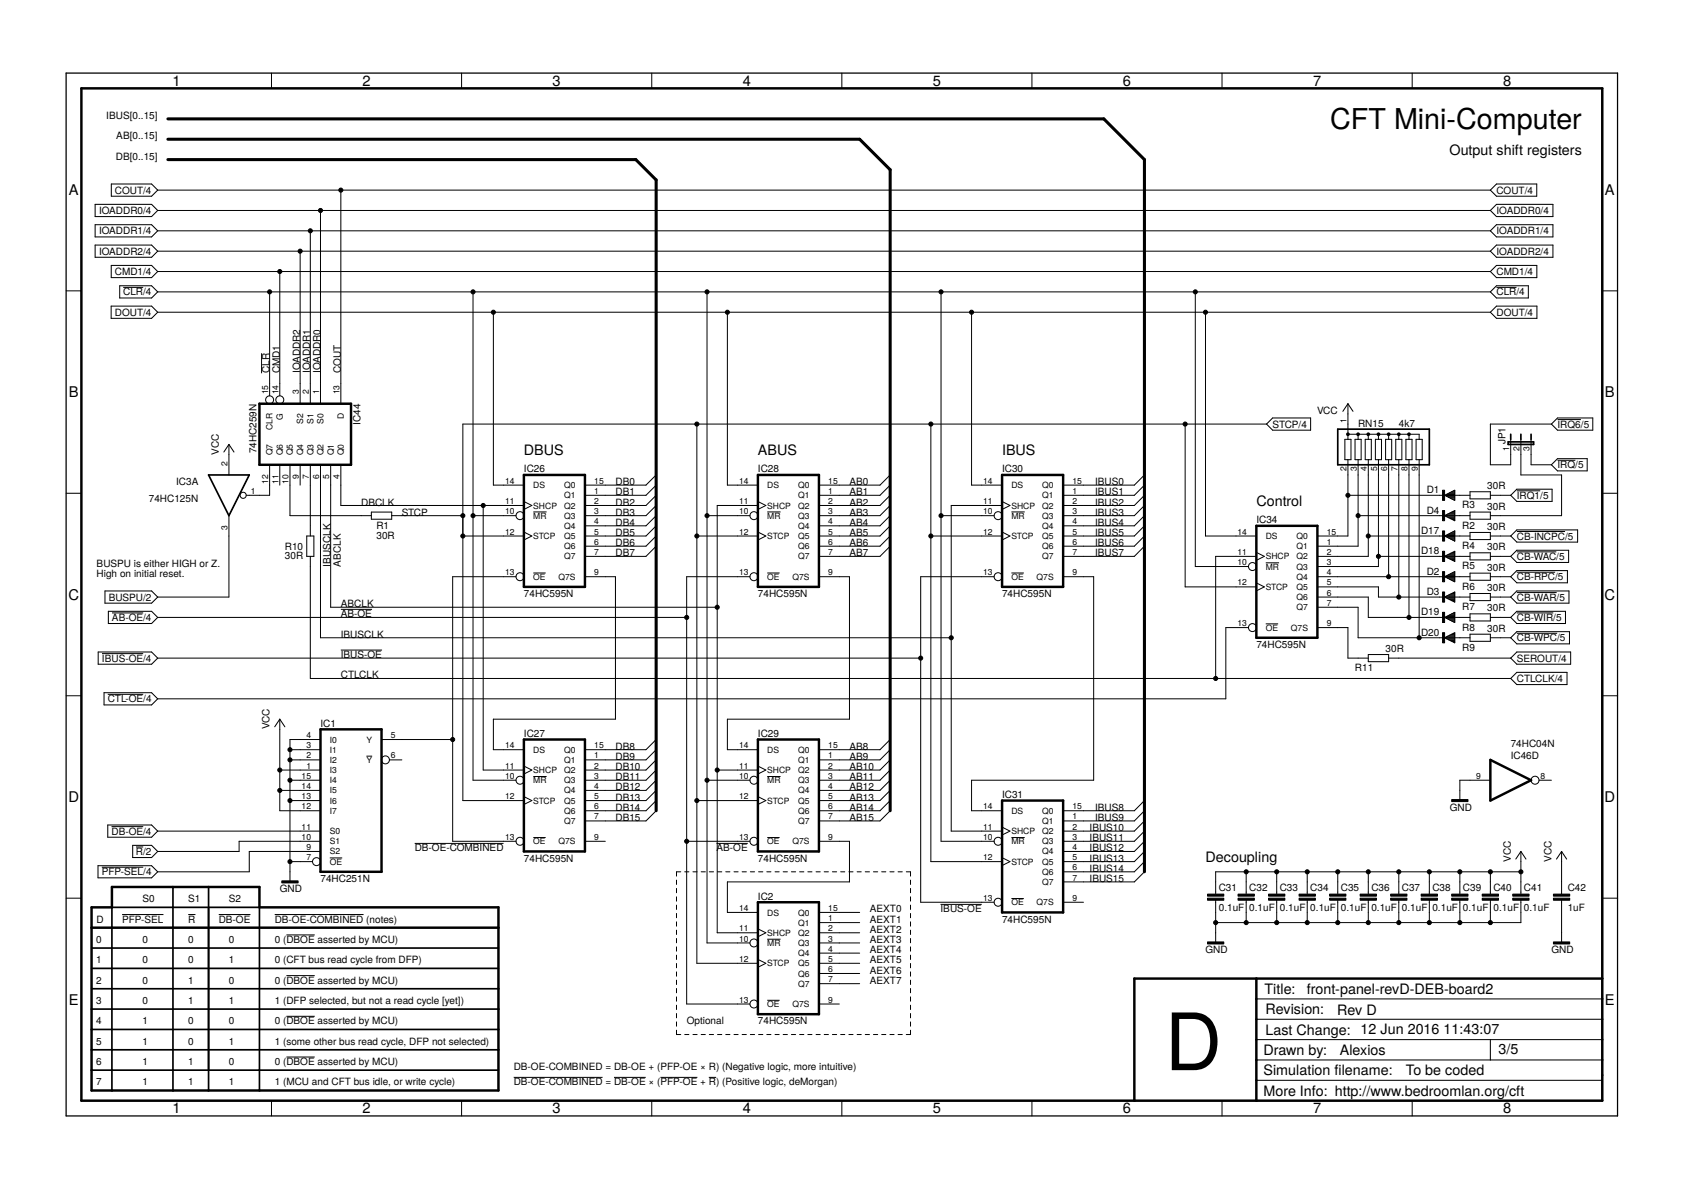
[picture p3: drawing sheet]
<svg xmlns="http://www.w3.org/2000/svg" width="420mm" height="297mm" viewBox="0 0 420 297" stroke-linecap="round" stroke-linejoin="round" font-family="sans-serif">
<defs><g id="words">
<text font-size="19.7" x="290.8" y="267.1">D</text>
<text font-size="7.2" x="332.1" y="32.2">CFT Mini-Computer</text>
<g font-size="3.7">
<text x="43" y="21.4">1</text>
<text x="90.5" y="21.4">2</text>
<text x="138" y="21.4">3</text>
<text x="185.4" y="21.4">4</text>
<text x="232.9" y="21.4">5</text>
<text x="280.3" y="21.4">6</text>
<text x="327.8" y="21.4">7</text>
<text x="375.3" y="21.4">8</text>
<text x="17.2" y="48.6">A</text>
<text x="400.7" y="48.6">A</text>
<text x="17.2" y="99.2">B</text>
<text x="400.7" y="99.2">B</text>
<text x="17.1" y="149.7">C</text>
<text x="400.6" y="149.7">C</text>
<text x="17.1" y="200.2">D</text>
<text x="400.6" y="200.2">D</text>
<text x="17.2" y="250.8">E</text>
<text x="400.7" y="250.8">E</text>
<text x="43" y="277.9">1</text>
<text x="90.5" y="277.9">2</text>
<text x="138" y="277.9">3</text>
<text x="185.4" y="277.9">4</text>
<text x="232.9" y="277.9">5</text>
<text x="280.3" y="277.9">6</text>
<text x="327.8" y="277.9">7</text>
<text x="375.3" y="277.9">8</text>
</g>
<g font-size="3.6">
<text x="361.9" y="38.6">Output shift registers</text>
<text x="130.8" y="113.5">DBUS</text>
<text x="189.2" y="113.5">ABUS</text>
<text x="250.2" y="113.5">IBUS</text>
<text x="313.7" y="126.2">Control</text>
<text x="301" y="215.1">Decoupling</text>
<text x="315.7" y="248.1">Title:</text>
<text x="326.2" y="248.2">front-panel-revD-DEB-board2</text>
<text x="315.9" y="253.2">Revision:</text>
<text x="333.8" y="253.3">Rev D</text>
<text x="315.4" y="263.3">Drawn by:</text>
<text x="315.9" y="258.2">Last Change: 12 Jun 2016</text>
<text x="334.5" y="263.3">Alexios</text>
<text x="360.4" y="258.1">11:43:07</text>
<text x="374.1" y="263.2">3/5</text>
<text x="315.4" y="268.4">Simulation flename:</text>
<text x="333.2" y="268.4">i</text>
<text x="351" y="268.4">To be coded</text>
<text x="315.4" y="273.5">More Info: http://www.bedroomlan.org/cft</text>
</g>
<g font-size="2.5">
<text x="26.5" y="29.7">IBUS[0..15]</text>
<text x="29" y="34.8">AB[0..15]</text>
<text x="28.9" y="39.8">DB[0..15]</text>
<text x="24.7" y="53.4">IOADDR0/4</text>
<text x="28.7" y="48.3">COUT/4</text>
<text x="373.6" y="53.4">IOADDR0/4</text>
<text x="373.6" y="48.3">COUT/4</text>
<text x="24.7" y="58.5">IOADDR1/4</text>
<text x="373.6" y="58.5">IOADDR1/4</text>
<text x="24.7" y="63.6">IOADDR2/4</text>
<text x="373.6" y="63.6">IOADDR2/4</text>
<text x="28.7" y="68.7">CMD1/4</text>
<text x="373.6" y="68.7">CMD1/4</text>
<text x="30.8" y="73.7">CLR/4</text>
<text x="373.6" y="73.7">CLR/4</text>
<text x="28.7" y="78.8">DOUT/4</text>
<text x="373.6" y="78.8">DOUT/4</text>
<text x="67.3" y="93.2" transform="rotate(-90 67.3 93.2)">CLR</text>
<text x="69.8" y="93.2" transform="rotate(-90 69.8 93.2)">CMD1</text>
<text x="74.9" y="93.2" transform="rotate(-90 74.9 93.2)">IOADDR2</text>
<text x="77.5" y="93.2" transform="rotate(-90 77.5 93.2)">IOADDR1</text>
<text x="80" y="93.2" transform="rotate(-90 80 93.2)">IOADDR0</text>
<text x="85.1" y="93.2" transform="rotate(-90 85.1 93.2)">COUT</text>
<text x="90" y="106.1" transform="rotate(-90 90 106.1)">IC44</text>
<text x="317.7" y="106.8">STCP/4</text>
<text x="328.8" y="103.3">VCC</text>
<text x="339.1" y="106.5">RN15</text>
<text x="349.2" y="106.5">4k7</text>
<text x="388.8" y="106.8">IRQ6/5</text>
<text x="54.6" y="113.5" transform="rotate(-90 54.6 113.5)">VCC</text>
<text x="64" y="113.2" transform="rotate(-90 64 113.2)">74HC259N</text>
<text x="375.9" y="110.9" transform="rotate(-90 375.9 110.9)">JP1</text>
<text x="130.8" y="117.9">IC26</text>
<text x="189.2" y="117.9">IC28</text>
<text x="250.2" y="117.9">IC30</text>
<text x="388.8" y="116.9">IRQ/5</text>
<text x="37.1" y="125.4">74HC125N</text>
<text x="44" y="121">IC3A</text>
<text x="153.7" y="121.1">DB0</text>
<text x="153.7" y="123.6">DB1</text>
<text x="212.1" y="121.1">AB0</text>
<text x="212.1" y="123.6">AB1</text>
<text x="273.4" y="121.1">IBUS0</text>
<text x="273.4" y="123.6">IBUS1</text>
<text x="356.2" y="123.2">D1</text>
<text x="371.3" y="122.1">30R</text>
<text x="378.7" y="124.5">IRQ1/5</text>
<text x="90.2" y="126.2">DBCLK</text>
<text x="94" y="132">R1</text>
<text x="100.3" y="128.7">STCP</text>
<text x="153.7" y="126.2">DB2</text>
<text x="153.7" y="128.7">DB3</text>
<text x="153.7" y="131.3">DB4</text>
<text x="212.1" y="126.2">AB2</text>
<text x="212.1" y="128.7">AB3</text>
<text x="212.1" y="131.3">AB4</text>
<text x="273.4" y="126.2">IBUS2</text>
<text x="273.4" y="128.7">IBUS3</text>
<text x="273.4" y="131.3">IBUS4</text>
<text x="313.7" y="130.6">IC34</text>
<text x="356.2" y="128.2">D4</text>
<text x="365.1" y="132">R2</text>
<text x="365.1" y="126.9">R3</text>
<text x="371.3" y="127.2">30R</text>
<text x="71.1" y="137.4">R10</text>
<text x="94" y="134.6">30R</text>
<text x="153.7" y="133.8">DB5</text>
<text x="153.7" y="136.3">DB6</text>
<text x="212.1" y="133.8">AB5</text>
<text x="212.1" y="136.3">AB6</text>
<text x="273.4" y="133.8">IBUS5</text>
<text x="273.4" y="136.3">IBUS6</text>
<text x="354.8" y="133.3">D17</text>
<text x="365.1" y="137.1">R4</text>
<text x="371.3" y="132.3">30R</text>
<text x="371.3" y="137.4">30R</text>
<text x="378.7" y="134.7">CB-INCPC/5</text>
<text x="24.1" y="141.4">BUSPU is either HIGH or Z.</text>
<text x="24.1" y="144">High on initial reset.</text>
<text x="71.1" y="139.6">30R</text>
<text x="82.5" y="141.4" transform="rotate(-90 82.5 141.4)">IBUSCLK</text>
<text x="85.1" y="141.4" transform="rotate(-90 85.1 141.4)">ABCLK</text>
<text x="153.7" y="138.9">DB7</text>
<text x="212.1" y="138.9">AB7</text>
<text x="273.4" y="138.9">IBUS7</text>
<text x="354.8" y="138.4">D18</text>
<text x="356.2" y="143.5">D2</text>
<text x="365.1" y="142.2">R5</text>
<text x="371.3" y="142.4">30R</text>
<text x="378.7" y="139.8">CB-WAC/5</text>
<text x="27.1" y="149.9">BUSPU/2</text>
<text x="130.8" y="149">74HC595N</text>
<text x="189.2" y="149">74HC595N</text>
<text x="250.2" y="149">74HC595N</text>
<text x="356.2" y="148.6">D3</text>
<text x="365.1" y="147.2">R6</text>
<text x="371.3" y="147.5">30R</text>
<text x="378.7" y="149.9">CB-WAR/5</text>
<text x="378.7" y="144.8">CB-RPC/5</text>
<text x="28" y="155">AB-OE/4</text>
<text x="85.1" y="151.6">ABCLK</text>
<text x="85.1" y="154.1">AB-OE</text>
<text x="354.8" y="153.6">D19</text>
<text x="365.1" y="152.3">R7</text>
<text x="371.3" y="152.6">30R</text>
<text x="378.7" y="155">CB-WIR/5</text>
<text x="85.1" y="159.2">IBUSCLK</text>
<text x="313.7" y="161.7">74HC595N</text>
<text x="354.8" y="158.7">D20</text>
<text x="365.1" y="157.4">R8</text>
<text x="371.3" y="157.7">30R</text>
<text x="378.7" y="160.1">CB-WPC/5</text>
<text x="25.5" y="165.2">IBUS-OE/4</text>
<text x="85.1" y="164.3">IBUS-OE</text>
<text x="338.3" y="167.5">R11</text>
<text x="345.9" y="162.8">30R</text>
<text x="365.1" y="162.5">R9</text>
<text x="378.7" y="165.2">SEROUT/4</text>
<text x="85.1" y="169.4">CTLCLK</text>
<text x="378.7" y="170.2">CTLCLK/4</text>
<text x="26.9" y="175.3">CTL-OE/4</text>
<text x="67.3" y="182.1" transform="rotate(-90 67.3 182.1)">VCC</text>
<text x="80" y="181.4">IC1</text>
<text x="130.8" y="184">IC27</text>
<text x="189.2" y="184">IC29</text>
<text x="153.7" y="187.1">DB8</text>
<text x="153.7" y="189.7">DB9</text>
<text x="212.1" y="187.1">AB8</text>
<text x="212.1" y="189.7">AB9</text>
<text x="377.1" y="186.4">74HC04N</text>
<text x="377.1" y="189.5">IC46D</text>
<text x="153.7" y="192.2">DB10</text>
<text x="153.7" y="194.7">DB11</text>
<text x="153.7" y="197.3">DB12</text>
<text x="212.1" y="192.2">AB10</text>
<text x="212.1" y="194.7">AB11</text>
<text x="212.1" y="197.3">AB12</text>
<text x="153.7" y="199.8">DB13</text>
<text x="153.7" y="202.4">DB14</text>
<text x="212.1" y="199.8">AB13</text>
<text x="212.1" y="202.4">AB14</text>
<text x="250.2" y="199.2">IC31</text>
<text x="273.4" y="202.4">IBUS8</text>
<text x="361.9" y="202.4">GND</text>
<text x="27.8" y="208.3">DB-OE/4</text>
<text x="153.7" y="204.9">DB15</text>
<text x="212.1" y="204.9">AB15</text>
<text x="272" y="207.4">IBUS10</text>
<text x="272" y="210">IBUS11</text>
<text x="273.4" y="204.9">IBUS9</text>
<text x="33.9" y="213.4">R/2</text>
<text x="103.5" y="212.5">DB-OE-COMBINED</text>
<text x="130.8" y="215.1">74HC595N</text>
<text x="178.9" y="212.5">AB-OE</text>
<text x="189.2" y="215.1">74HC595N</text>
<text x="272" y="212.5">IBUS12</text>
<text x="272" y="215.1">IBUS13</text>
<text x="377.1" y="215.1" transform="rotate(-90 377.1 215.1)">VCC</text>
<text x="387.3" y="215.1" transform="rotate(-90 387.3 215.1)">VCC</text>
<text x="25.4" y="218.5">PFP-SEL/4</text>
<text x="80" y="220.1">74HC251N</text>
<text x="272" y="217.6">IBUS14</text>
<text x="272" y="220.1">IBUS15</text>
<text x="35.6" y="225.2">S0</text>
<text x="47" y="225.2">S1</text>
<text x="57.1" y="225.2">S2</text>
<text x="69.8" y="222.7">GND</text>
<text x="189.2" y="224.6">IC2</text>
<text x="217.1" y="227.8">AEXT0</text>
<text x="234.8" y="227.8">IBUS-OE</text>
<text x="304.3" y="227.4">0.1uF</text>
<text x="304.3" y="222.3">C31</text>
<text x="311.9" y="227.4">0.1uF</text>
<text x="311.9" y="222.3">C32</text>
<text x="319.5" y="227.4">0.1uF</text>
<text x="319.5" y="222.3">C33</text>
<text x="327.1" y="227.4">0.1uF</text>
<text x="327.1" y="222.3">C34</text>
<text x="334.7" y="227.4">0.1uF</text>
<text x="334.7" y="222.3">C35</text>
<text x="342.4" y="227.4">0.1uF</text>
<text x="342.4" y="222.3">C36</text>
<text x="350" y="227.4">0.1uF</text>
<text x="350" y="222.3">C37</text>
<text x="357.6" y="227.4">0.1uF</text>
<text x="357.6" y="222.3">C38</text>
<text x="365.2" y="227.4">0.1uF</text>
<text x="365.2" y="222.3">C39</text>
<text x="372.8" y="227.4">0.1uF</text>
<text x="372.8" y="222.3">C40</text>
<text x="380.4" y="227.4">0.1uF</text>
<text x="380.4" y="222.3">C41</text>
<text x="391.4" y="227.4">1uF</text>
<text x="391.4" y="222.3">C42</text>
<text x="24.1" y="230.3">D</text>
<text x="30.5" y="230.3">PFP-SEL</text>
<text x="47" y="230.3">R</text>
<text x="54.6" y="230.3">DB-OE</text>
<text x="68.6" y="230.3">DB-OE-COMBINED (notes)</text>
<text x="217.1" y="230.3">AEXT1</text>
<text x="217.1" y="232.8">AEXT2</text>
<text x="250.2" y="230.3">74HC595N</text>
<text x="24" y="235.4">0</text>
<text x="35.6" y="235.4">0</text>
<text x="47" y="235.4">0</text>
<text x="57.1" y="235.4">0</text>
<text x="68.6" y="235.4">0 (DBOE asserted by MCU)</text>
<text x="217.1" y="235.4">AEXT3</text>
<text x="217.1" y="237.9">AEXT4</text>
<text x="301" y="237.9">GND</text>
<text x="387.3" y="237.9">GND</text>
<text x="24" y="245.5">2</text>
<text x="24" y="240.5">1</text>
<text x="35.6" y="245.5">0</text>
<text x="35.6" y="240.5">0</text>
<text x="47" y="240.5">0</text>
<text x="47" y="245.5">1</text>
<text x="57.1" y="240.5">1</text>
<text x="57.1" y="245.5">0</text>
<text x="68.6" y="245.5">0 (DBOE asserted by MCU)</text>
<text x="68.6" y="240.5">0 (CFT bus read cycle from DFP)</text>
<text x="217.1" y="240.5">AEXT5</text>
<text x="217.1" y="245.5">AEXT7</text>
<text x="217.1" y="243">AEXT6</text>
<text x="24" y="250.6">3</text>
<text x="35.6" y="250.6">0</text>
<text x="47" y="250.6">1</text>
<text x="57.1" y="250.6">1</text>
<text x="68.6" y="250.6">1 (DFP selected, but not a read cycle [yet])</text>
<text x="24" y="255.7">4</text>
<text x="35.6" y="255.7">1</text>
<text x="47" y="255.7">0</text>
<text x="57.1" y="255.7">0</text>
<text x="68.6" y="255.7">0 (DBOE asserted by MCU)</text>
<text x="171.4" y="255.7">Optional</text>
<text x="189.2" y="255.7">74HC595N</text>
<text x="24" y="260.8">5</text>
<text x="35.6" y="260.8">1</text>
<text x="47" y="260.8">0</text>
<text x="57.1" y="260.8">1</text>
<text x="68.6" y="260.8">1 (some other bus read cycle, DFP not selected)</text>
<text x="24" y="265.9">6</text>
<text x="35.6" y="265.9">1</text>
<text x="47" y="265.9">1</text>
<text x="57.1" y="265.9">0</text>
<text x="68.6" y="265.9">0 (DBOE asserted by MCU)</text>
<text x="128.3" y="267.1">DB-OE-COMBINED = DB-OE + (PFP-OE × R) (Negative logic, more intuitive)</text>
<text x="24" y="270.9">7</text>
<text x="35.6" y="270.9">1</text>
<text x="47" y="270.9">1</text>
<text x="57.1" y="270.9">1</text>
<text x="68.6" y="270.9">1 (MCU and CFT bus idle, or write cycle)</text>
<text x="128.3" y="270.9">DB-OE-COMBINED = DB-OE × (PFP-OE + R) (Positive logic, deMorgan)</text>
</g>
<g font-size="2.1">
<text x="66.9" y="98.4" transform="rotate(-90 66.9 98.4)">15</text>
<text x="69.5" y="98.4" transform="rotate(-90 69.5 98.4)">14</text>
<text x="74.6" y="98.4" transform="rotate(-90 74.6 98.4)">3</text>
<text x="77.1" y="98.4" transform="rotate(-90 77.1 98.4)">2</text>
<text x="79.6" y="98.4" transform="rotate(-90 79.6 98.4)">1</text>
<text x="84.7" y="98.4" transform="rotate(-90 84.7 98.4)">13</text>
<text x="68.1" y="107.4" transform="rotate(-90 68.1 107.4)">CLR</text>
<text x="70.6" y="104.8" transform="rotate(-90 70.6 104.8)">G</text>
<text x="75.7" y="105.7" transform="rotate(-90 75.7 105.7)">S2</text>
<text x="78.2" y="105.7" transform="rotate(-90 78.2 105.7)">S1</text>
<text x="80.8" y="105.7" transform="rotate(-90 80.8 105.7)">S0</text>
<text x="85.8" y="104.7" transform="rotate(-90 85.8 104.7)">D</text>
<text x="336.2" y="105.5" transform="rotate(-90 336.2 105.5)">1</text>
<text x="68.1" y="113.7" transform="rotate(-90 68.1 113.7)">Q7</text>
<text x="70.6" y="113.7" transform="rotate(-90 70.6 113.7)">Q6</text>
<text x="73.1" y="113.7" transform="rotate(-90 73.1 113.7)">Q5</text>
<text x="75.7" y="113.7" transform="rotate(-90 75.7 113.7)">Q4</text>
<text x="78.2" y="113.7" transform="rotate(-90 78.2 113.7)">Q3</text>
<text x="80.8" y="113.7" transform="rotate(-90 80.8 113.7)">Q2</text>
<text x="83.3" y="113.7" transform="rotate(-90 83.3 113.7)">Q1</text>
<text x="85.8" y="113.7" transform="rotate(-90 85.8 113.7)">Q0</text>
<text x="376.8" y="112.5" transform="rotate(-90 376.8 112.5)">1</text>
<text x="379.3" y="112.5" transform="rotate(-90 379.3 112.5)">2</text>
<text x="381.9" y="112.5" transform="rotate(-90 381.9 112.5)">3</text>
<text x="56.8" y="116.2" transform="rotate(-90 56.8 116.2)">2</text>
<text x="74.6" y="119.5" transform="rotate(-90 74.6 119.5)">9</text>
<text x="77.1" y="119.5" transform="rotate(-90 77.1 119.5)">7</text>
<text x="79.6" y="119.5" transform="rotate(-90 79.6 119.5)">6</text>
<text x="82.2" y="119.5" transform="rotate(-90 82.2 119.5)">5</text>
<text x="84.7" y="119.5" transform="rotate(-90 84.7 119.5)">4</text>
<text x="336.2" y="117.6" transform="rotate(-90 336.2 117.6)">2</text>
<text x="338.7" y="117.6" transform="rotate(-90 338.7 117.6)">3</text>
<text x="341.2" y="117.6" transform="rotate(-90 341.2 117.6)">4</text>
<text x="343.8" y="117.6" transform="rotate(-90 343.8 117.6)">5</text>
<text x="346.3" y="117.6" transform="rotate(-90 346.3 117.6)">6</text>
<text x="348.9" y="117.6" transform="rotate(-90 348.9 117.6)">7</text>
<text x="351.4" y="117.6" transform="rotate(-90 351.4 117.6)">8</text>
<text x="353.9" y="117.6" transform="rotate(-90 353.9 117.6)">9</text>
<text x="62.6" y="123.3">1</text>
<text x="66.9" y="120.7" transform="rotate(-90 66.9 120.7)">12</text>
<text x="69.5" y="120.7" transform="rotate(-90 69.5 120.7)">11</text>
<text x="72" y="120.7" transform="rotate(-90 72 120.7)">10</text>
<text x="126.1" y="125.8">11</text>
<text x="126.1" y="120.7">14</text>
<text x="133.1" y="121.9">DS</text>
<text x="140.8" y="124.4">Q1</text>
<text x="140.8" y="121.9">Q0</text>
<text x="148.4" y="123.3">1</text>
<text x="148.4" y="125.8">2</text>
<text x="148.4" y="120.7">15</text>
<text x="184.5" y="125.8">11</text>
<text x="184.5" y="120.7">14</text>
<text x="191.5" y="121.9">DS</text>
<text x="199.3" y="124.4">Q1</text>
<text x="199.3" y="121.9">Q0</text>
<text x="206.8" y="123.3">1</text>
<text x="206.8" y="125.8">2</text>
<text x="206.8" y="120.7">15</text>
<text x="245.5" y="125.8">11</text>
<text x="245.5" y="120.7">14</text>
<text x="252.5" y="121.9">DS</text>
<text x="260.2" y="124.4">Q1</text>
<text x="260.2" y="121.9">Q0</text>
<text x="267.7" y="123.3">1</text>
<text x="267.7" y="125.8">2</text>
<text x="267.7" y="120.7">15</text>
<text x="126.1" y="128.4">10</text>
<text x="133.1" y="129.5">MR</text>
<text x="133.1" y="126.9">SHCP</text>
<text x="140.8" y="126.9">Q2</text>
<text x="140.8" y="129.5">Q3</text>
<text x="148.4" y="128.4">3</text>
<text x="148.4" y="130.9">4</text>
<text x="184.5" y="128.4">10</text>
<text x="191.5" y="129.5">MR</text>
<text x="191.5" y="126.9">SHCP</text>
<text x="199.3" y="126.9">Q2</text>
<text x="199.3" y="129.5">Q3</text>
<text x="206.8" y="128.4">3</text>
<text x="206.8" y="130.9">4</text>
<text x="245.5" y="128.4">10</text>
<text x="252.5" y="129.5">MR</text>
<text x="252.5" y="126.9">SHCP</text>
<text x="260.2" y="126.9">Q2</text>
<text x="260.2" y="129.5">Q3</text>
<text x="267.7" y="128.4">3</text>
<text x="267.7" y="130.9">4</text>
<text x="56.8" y="132.2" transform="rotate(-90 56.8 132.2)">3</text>
<text x="126.1" y="133.4">12</text>
<text x="133.1" y="134.6">STCP</text>
<text x="140.8" y="132">Q4</text>
<text x="140.8" y="134.6">Q5</text>
<text x="140.8" y="137.1">Q6</text>
<text x="148.4" y="133.4">5</text>
<text x="148.4" y="136">6</text>
<text x="184.5" y="133.4">12</text>
<text x="191.5" y="134.6">STCP</text>
<text x="199.3" y="132">Q4</text>
<text x="199.3" y="134.6">Q5</text>
<text x="199.3" y="137.1">Q6</text>
<text x="206.8" y="133.4">5</text>
<text x="206.8" y="136">6</text>
<text x="245.5" y="133.4">12</text>
<text x="252.5" y="134.6">STCP</text>
<text x="260.2" y="132">Q4</text>
<text x="260.2" y="134.6">Q5</text>
<text x="260.2" y="137.1">Q6</text>
<text x="267.7" y="133.4">5</text>
<text x="267.7" y="136">6</text>
<text x="308.9" y="133.4">14</text>
<text x="316" y="134.6">DS</text>
<text x="323.7" y="137.1">Q1</text>
<text x="323.7" y="134.6">Q0</text>
<text x="331.2" y="136">1</text>
<text x="331.2" y="133.4">15</text>
<text x="126.1" y="143.6">13</text>
<text x="140.8" y="139.6">Q7</text>
<text x="148.4" y="138.5">7</text>
<text x="148.4" y="143.6">9</text>
<text x="184.5" y="143.6">13</text>
<text x="199.3" y="139.6">Q7</text>
<text x="206.8" y="138.5">7</text>
<text x="206.8" y="143.6">9</text>
<text x="245.5" y="143.6">13</text>
<text x="260.2" y="139.6">Q7</text>
<text x="267.7" y="138.5">7</text>
<text x="267.7" y="143.6">9</text>
<text x="308.9" y="141.1">10</text>
<text x="308.9" y="138.5">11</text>
<text x="316" y="142.2">MR</text>
<text x="316" y="139.6">SHCP</text>
<text x="323.7" y="139.6">Q2</text>
<text x="323.7" y="142.2">Q3</text>
<text x="331.2" y="138.5">2</text>
<text x="331.2" y="141.1">3</text>
<text x="331.2" y="143.6">4</text>
<text x="133.1" y="144.7">OE</text>
<text x="139.4" y="144.7">Q7S</text>
<text x="191.5" y="144.7">OE</text>
<text x="197.8" y="144.7">Q7S</text>
<text x="252.5" y="144.7">OE</text>
<text x="258.8" y="144.7">Q7S</text>
<text x="308.9" y="146.1">12</text>
<text x="316" y="147.3">STCP</text>
<text x="323.7" y="144.7">Q4</text>
<text x="323.7" y="147.3">Q5</text>
<text x="323.7" y="149.8">Q6</text>
<text x="331.2" y="146.1">5</text>
<text x="331.2" y="148.7">6</text>
<text x="323.7" y="152.3">Q7</text>
<text x="331.2" y="151.2">7</text>
<text x="308.9" y="156.3">13</text>
<text x="316" y="157.4">OE</text>
<text x="322.3" y="157.4">Q7S</text>
<text x="331.2" y="156.3">9</text>
<text x="76.5" y="184.2">4</text>
<text x="82.3" y="185.4">I0</text>
<text x="91.5" y="185.4">Y</text>
<text x="97.6" y="184.2">5</text>
<text x="76.5" y="191.9">1</text>
<text x="76.5" y="189.3">2</text>
<text x="76.5" y="186.8">3</text>
<text x="82.3" y="190.4">I2</text>
<text x="82.3" y="187.9">I1</text>
<text x="91.5" y="190.4">Y</text>
<text x="97.6" y="189.3">6</text>
<text x="126.1" y="191.9">11</text>
<text x="126.1" y="186.8">14</text>
<text x="133.1" y="187.9">DS</text>
<text x="140.8" y="190.4">Q1</text>
<text x="140.8" y="187.9">Q0</text>
<text x="148.4" y="189.3">1</text>
<text x="148.4" y="191.9">2</text>
<text x="148.4" y="186.8">15</text>
<text x="184.5" y="191.9">11</text>
<text x="184.5" y="186.8">14</text>
<text x="191.5" y="187.9">DS</text>
<text x="199.3" y="190.4">Q1</text>
<text x="199.3" y="187.9">Q0</text>
<text x="206.8" y="189.3">1</text>
<text x="206.8" y="191.9">2</text>
<text x="206.8" y="186.8">15</text>
<text x="75.3" y="196.9">14</text>
<text x="75.3" y="194.4">15</text>
<text x="82.3" y="193">I3</text>
<text x="82.3" y="195.5">I4</text>
<text x="126.1" y="194.4">10</text>
<text x="133.1" y="195.5">MR</text>
<text x="133.1" y="193">SHCP</text>
<text x="140.8" y="193">Q2</text>
<text x="140.8" y="195.5">Q3</text>
<text x="148.4" y="194.4">3</text>
<text x="148.4" y="196.9">4</text>
<text x="184.5" y="194.4">10</text>
<text x="191.5" y="195.5">MR</text>
<text x="191.5" y="193">SHCP</text>
<text x="199.3" y="193">Q2</text>
<text x="199.3" y="195.5">Q3</text>
<text x="206.8" y="194.4">3</text>
<text x="206.8" y="196.9">4</text>
<text x="368.5" y="194.4">9</text>
<text x="384.6" y="194.4">8</text>
<text x="75.3" y="202">12</text>
<text x="75.3" y="199.5">13</text>
<text x="82.3" y="203.1">I7</text>
<text x="82.3" y="200.6">I6</text>
<text x="82.3" y="198">I5</text>
<text x="126.1" y="199.5">12</text>
<text x="133.1" y="200.6">STCP</text>
<text x="140.8" y="198">Q4</text>
<text x="140.8" y="200.6">Q5</text>
<text x="140.8" y="203.1">Q6</text>
<text x="148.4" y="199.5">5</text>
<text x="148.4" y="202">6</text>
<text x="184.5" y="199.5">12</text>
<text x="191.5" y="200.6">STCP</text>
<text x="199.3" y="198">Q4</text>
<text x="199.3" y="200.6">Q5</text>
<text x="199.3" y="203.1">Q6</text>
<text x="206.8" y="199.5">5</text>
<text x="206.8" y="202">6</text>
<text x="245.5" y="202">14</text>
<text x="252.5" y="203.1">DS</text>
<text x="260.2" y="203.1">Q0</text>
<text x="267.7" y="202">15</text>
<text x="75.3" y="209.6">10</text>
<text x="75.3" y="207.1">11</text>
<text x="82.3" y="208.2">S0</text>
<text x="126.1" y="209.6">13</text>
<text x="140.8" y="205.7">Q7</text>
<text x="148.4" y="204.6">7</text>
<text x="148.4" y="209.6">9</text>
<text x="184.5" y="209.6">13</text>
<text x="199.3" y="205.7">Q7</text>
<text x="206.8" y="204.6">7</text>
<text x="206.8" y="209.6">9</text>
<text x="245.5" y="209.6">10</text>
<text x="245.5" y="207.1">11</text>
<text x="252.5" y="208.2">SHCP</text>
<text x="260.2" y="205.7">Q1</text>
<text x="260.2" y="208.2">Q2</text>
<text x="267.7" y="204.6">1</text>
<text x="267.7" y="207.1">2</text>
<text x="267.7" y="209.6">3</text>
<text x="76.5" y="214.7">7</text>
<text x="76.5" y="212.2">9</text>
<text x="82.3" y="215.8">OE</text>
<text x="82.3" y="213.3">S2</text>
<text x="82.3" y="210.7">S1</text>
<text x="133.1" y="210.7">OE</text>
<text x="139.4" y="210.7">Q7S</text>
<text x="191.5" y="210.7">OE</text>
<text x="197.8" y="210.7">Q7S</text>
<text x="245.5" y="214.7">12</text>
<text x="252.5" y="210.7">MR</text>
<text x="252.5" y="215.8">STCP</text>
<text x="260.2" y="210.7">Q3</text>
<text x="260.2" y="213.3">Q4</text>
<text x="260.2" y="215.8">Q5</text>
<text x="267.7" y="212.2">4</text>
<text x="267.7" y="214.7">5</text>
<text x="260.2" y="218.4">Q6</text>
<text x="260.2" y="220.9">Q7</text>
<text x="267.7" y="217.2">6</text>
<text x="267.7" y="219.8">7</text>
<text x="184.5" y="227.4">14</text>
<text x="206.8" y="227.4">15</text>
<text x="245.5" y="224.9">13</text>
<text x="252.5" y="226">OE</text>
<text x="258.8" y="226">Q7S</text>
<text x="267.7" y="224.9">9</text>
<text x="184.5" y="232.5">11</text>
<text x="191.5" y="233.6">SHCP</text>
<text x="191.5" y="228.5">DS</text>
<text x="199.3" y="231.1">Q1</text>
<text x="199.3" y="233.6">Q2</text>
<text x="199.3" y="228.5">Q0</text>
<text x="206.8" y="229.9">1</text>
<text x="206.8" y="232.5">2</text>
<text x="184.5" y="235">10</text>
<text x="191.5" y="236.1">MR</text>
<text x="199.3" y="236.1">Q3</text>
<text x="199.3" y="238.7">Q4</text>
<text x="206.8" y="235">3</text>
<text x="206.8" y="237.6">4</text>
<text x="184.5" y="240.1">12</text>
<text x="191.5" y="241.2">STCP</text>
<text x="199.3" y="241.2">Q5</text>
<text x="199.3" y="243.8">Q6</text>
<text x="206.8" y="240.1">5</text>
<text x="206.8" y="242.6">6</text>
<text x="206.8" y="245.2">7</text>
<text x="184.5" y="250.3">13</text>
<text x="191.5" y="251.4">OE</text>
<text x="197.8" y="251.4">Q7S</text>
<text x="199.3" y="246.3">Q7</text>
<text x="206.8" y="250.3">9</text>
</g>
</g></defs>
<g fill="none" stroke="#000" stroke-width=".25">
<path d="M67.8 18.2v3.9M115.2 18.2v3.9M162.7 18.2v3.9M210.2 18.2v3.9M257.6 18.2v3.9M305.1 18.2v3.9M352.6 18.2v3.9M20.3 22.1h379.7v252.6h-379.7zM23.7 51h14.1l1.6 1.5-1.6 1.6h-14.1zM23.7 56.1h14.1l1.6 1.5-1.6 1.5h-14.1zM27.8 45.9h10l1.6 1.6-1.6 1.5h-10zM39.4 52.5h332.7"/>
<path d="M39.4 57.6h332.7M39.4 47.5h332.7M77.5 57.6v43.2M80 52.5v48.3M85.1 47.5v53.3M372.1 52.5l1.5-1.5h14.1v3.1h-14.1zM372.1 57.6l1.5-1.5h14.1v3h-14.1zM372.1 47.5l1.5-1.6h10v3.1h-10zM16.5 72.6h3.8M23.7 61.2h14.1l1.6 1.5-1.6 1.5h-14.1zM27.7 76.4h10.1l1.6 1.5-1.6 1.6h-10.1zM27.8 66.3h10l1.6 1.5-1.6 1.5h-10z"/>
<path d="M29.9 71.3h7.9l1.6 1.6-1.6 1.5h-7.9zM30.8 71.7h5M39.4 77.9h332.7M39.4 72.9h332.7M39.4 62.7h332.7M39.4 67.8h332.7M67.3 72.9v25.9M69.8 67.8v31M74.9 62.7v38.1M118.1 72.9v121.9h10.7M123.2 77.9v43.2h7.6M176.5 72.9v162.5h10.7"/>
<path d="M181.6 77.9v43.2h7.6M234.9 72.9v137.1h13.3M242.5 77.9v43.2h7.7M298.4 72.9v68.5h13.3M300.9 77.9v55.9h12.7M372.1 62.7l1.5-1.5h14.1v3h-14.1zM373.6 76.4h10.1v3.1h-10.1l-1.5-1.6zM373.6 71.3h8v3.1h-8l-1.5-1.5zM373.6 71.7h5M373.6 66.3h10.1v3h-10.1l-1.5-1.5zM400 72.6h3.8M65.3 88.2v5"/>
<path d="M57.1 110.9v7.7M57.1 110.9l1.3 1.9M57.1 110.9l-1.2 1.9M67.3 116v7.6h-5.8M69.8 116v5.1M72.4 116v12.7h20.3M74.9 116v5.1M77.5 116v17.8M80 116v43.2h157.5M82.5 116v35.6h96.5M85.1 116v10.2h45.7M163.8 118.6l-2.5 2.5h-15.3"/>
<path d="M174 105.9v134.6h15.2M222.2 118.6l-2.5 2.5h-15.3M232.4 105.9v109.2h17.8M285.7 118.6l-2.5 2.5h-17.8M295.9 105.9v40.6h17.7M316.2 105.9h-200.7v93.9h15.3M317.7 104.3h9.5v3.1h-9.5l-1.5-1.5zM335.7 109.7h1.6v5h-1.6zM336.5 114.7v19.1h-7.6M336.5 100.8v8.9M336.5 108.4h17.8v1.3M336.5 100.8l-1.3 1.9"/>
<path d="M336.5 100.8l1.3 1.9M338.3 109.7h1.5v5h-1.5zM339 114.7v21.6h-10.1M339 108.4v1.3M340.8 109.7h1.5v5h-1.5zM341.6 114.7v24.2h-12.7M341.6 108.4v1.3M343.4 109.7h1.5v5h-1.5zM344.1 114.7v26.7h-15.2M344.1 108.4v1.3M345.9 109.7h1.5v5h-1.5zM346.7 108.4v1.3"/>
<path d="M346.7 114.7v29.3M348.4 109.7h1.6v5h-1.6zM349.2 108.4v1.3M349.2 114.7v34.3M351 109.7h1.5v5h-1.5zM351.7 108.4v1.3M351.7 114.7v39.4M353.5 109.7h1.5v5h-1.5zM354.3 114.7v44.5M379.7 109.7v8.9h10.1v10.1h-17.7M382.2 109.7v6.3h5.1M387.3 105.9l1.5-1.6h8.8v3.1h-8.8z"/>
<path d="M387.3 105.9h-15.2v10.1h5v-6.3M388.8 114.5h7.4v3h-7.4l-1.5-1.5zM388.8 114.9h4.5M388.8 104.7h5.9M16.5 123.1h3.8M57.1 128.7v20.3h-17.7M76.6 133.8h1.8v5.1h-1.8zM77.5 138.9v30.5h299.6M92.7 127.8h5.1v1.8h-5.1zM97.8 128.7h17.7M115.5 133.8h15.3M118.1 128.7h10.7"/>
<path d="M120.6 126.2v66h10.2M130.8 125.2l2 1-2 1M130.8 132.8l2 1-2 1M133.1 127.8h3.4M163.8 121.1l-2.5 2.5h-15.3M163.8 123.6l-2.5 2.6h-15.3M163.8 126.2l-2.5 2.5h-15.3M163.8 128.7l-2.5 2.6h-15.3M163.8 131.3l-2.5 2.5h-15.3M163.8 133.8l-2.5 2.5h-15.3M163.8 136.3l-2.5 2.6h-15.3M174 133.8h15.2"/>
<path d="M176.5 128.7h10.7M189.2 126.2h-10.2v106.6h10.2M189.2 125.2l2 1-2 1M189.2 132.8l2 1-2 1M191.5 127.8h3.4M222.2 121.1l-2.5 2.5h-15.3M222.2 123.6l-2.5 2.6h-15.3M222.2 126.2l-2.5 2.5h-15.3M222.2 128.7l-2.5 2.6h-15.3M222.2 131.3l-2.5 2.5h-15.3M222.2 133.8l-2.5 2.5h-15.3M222.2 136.3l-2.5 2.6h-15.3"/>
<path d="M232.4 133.8h17.8M234.9 128.7h13.3M250.2 126.2h-12.7v81.3h12.7M250.2 125.2l1.9 1-1.9 1M250.2 132.8l1.9 1-1.9 1M252.5 127.8h3.3M285.7 121.1l-2.5 2.5h-17.8M285.7 123.6l-2.5 2.6h-17.8M285.7 126.2l-2.5 2.5h-17.8M285.7 128.7l-2.5 2.6h-17.8M285.7 131.3l-2.5 2.5h-17.8M285.7 133.8l-2.5 2.5h-17.8"/>
<path d="M285.7 136.3l-2.5 2.6h-17.8M313.6 138.9h-10.1v30.5M313.6 137.9l2 1-2 1M336.5 123.6h30.5M339 128.7h28M341.6 133.8h25.4M344.1 138.9h22.9M360.6 133.8l2.6-1.3v2.6zM360.6 123.6l2.6-1.2v2.5zM360.6 128.7l2.6-1.3v2.6zM360.6 138.9l2.6-1.3v2.5zM360.7 123.7h2.5"/>
<path d="M360.8 128.8h2.4M360.8 133.9h2.4M360.8 138.8h2.4M360.9 133.7h2.3M360.9 139h2.3M361 128.6h2.2M361 123.4h2.2M361.1 123.9h2.1M361.2 129h2M361.3 134.1h1.9M361.3 138.6h1.9M361.3 133.5h1.9"/>
<path d="M361.3 139.2h1.9M361.4 128.3h1.8M361.5 123.2h1.7M361.6 124.1h1.6M361.7 129.2h1.5M361.7 134.3h1.5M361.7 138.3h1.5M361.8 133.2h1.4M361.8 139.4h1.4M361.8 128.1h1.4M361.9 123h1.3M362 124.3h1.2"/>
<path d="M362.1 129.5h1.1M362.2 134.6h1M362.2 138.1h1M362.2 133h1M362.2 139.7h1M362.3 127.9h.9M362.4 122.8h.8M362.5 124.6h.7M362.5 129.7h.7M362.6 134.8h.6M362.6 137.9h.6M362.7 132.8h.5"/>
<path d="M362.7 139.9h.5M362.7 127.7h.5M362.8 122.6h.4M362.9 124.8h.3M363 129.9h.2M363.1 135h.1M363.1 137.7h.1M363.1 132.6h.1M363.2 127.4h.1M367 122.7h5.1v1.8h-5.1zM367 127.8h5.1v1.8h-5.1zM367 132.9h5.1v1.8h-5.1z"/>
<path d="M367 138h5.1v1.8h-5.1zM372.1 123.6h5M372.1 133.8h5M372.1 138.9h5M378.7 137.4h12.9v3h-12.9l-1.6-1.5zM378.7 137.8h9.8M378.7 132.3h15.1v3h-15.1l-1.6-1.5zM378.7 132.7h12M378.7 122.1h8.8v3.1h-8.8l-1.6-1.6zM378.7 122.5h5.8M400 123.1h3.8M26.2 147.5h11.6l1.6 1.5-1.6 1.6h-11.6z"/>
<path d="M27.1 152.6h10.7l1.6 1.5-1.6 1.5h-10.7zM28 153h7.8M39.4 154.1h132M85.1 152.1h7.8M128.8 144h-15.8v66h15.8M133.1 143h3.1M146 144h7.6v35.5h-30.4v7.6h7.6M187.2 144h-15.8v106.6h15.8M191.5 143h3.1M204.4 144h7.7v35.5h-30.5v7.6h7.6M248.2 144h-18.4v81.2h18.4M252.5 143h3.1"/>
<path d="M265.4 144h7.6v50.8h-30.5v7.6h7.7M311.7 156.7h-5.7v17.7h-266.6M313.6 145.5l2 1-2 1M316 140.5h3.3M316 155.7h3.1M328.9 144h38.1M328.9 146.5h15.2v2.5h22.9M328.9 149h12.7v5.1h25.4M328.9 151.6h10.1v7.6h28M328.9 156.7h7.6v7.6h5.1M360.6 144l2.6-1.3v2.5zM360.6 149l2.6-1.2v2.5z"/>
<path d="M360.6 154.1l2.6-1.3v2.6zM360.6 159.2l2.6-1.3v2.6zM360.8 143.9h2.4M361 144.1h2.2M361 159h2.2M361 149.2h2.2M361.1 154.3h2.1M361.1 153.9h2.1M361.1 159.4h2.1M361.1 148.8h2.1M361.2 143.7h2M361.4 144.3h1.8"/>
<path d="M361.5 158.8h1.7M361.5 149.5h1.7M361.5 154.6h1.7M361.5 153.7h1.7M361.6 159.7h1.6M361.6 148.6h1.6M361.7 143.4h1.5M361.8 144.6h1.4M361.9 158.6h1.3M361.9 149.7h1.3M362 154.8h1.2M362 153.5h1.2"/>
<path d="M362 159.9h1.2M362 148.3h1.2M362.1 143.2h1.1M362.3 144.8h.9M362.4 158.3h.8M362.4 149.9h.8M362.4 155h.8M362.4 153.2h.8M362.5 148.1h.7M362.5 143h.7M362.7 145h.5M362.8 158.1h.4"/>
<path d="M362.8 150.1h.4M362.9 155.2h.3M362.9 153h.3M362.9 147.9h.3M363 142.8h.2M363.1 140.1h.1M367 143.1h5.1v1.7h-5.1zM367 148.1h5.1v1.8h-5.1zM367 153.2h5.1v1.8h-5.1zM367 158.3h5.1v1.8h-5.1zM372.1 144h5M372.1 149h5"/>
<path d="M372.1 154.1h5M372.1 159.2h5M377.1 154.1l1.6-1.5h12.1v3h-12.1zM378.7 153h9.1M378.7 147.5h13v3.1h-13l-1.6-1.6zM378.7 147.9h9.9M378.7 142.4h12.6v3.1h-12.6l-1.6-1.5zM378.7 142.8h9.5M378.7 157.7h13.1v3h-13.1l-1.6-1.5zM378.7 158.1h10M16.5 173.7h3.8M24.5 162.8h13.3l1.6 1.5-1.6 1.5h-13.3z"/>
<path d="M25.5 163.2h10.3M26 172.9h11.8l1.6 1.5-1.6 1.6h-11.8zM26.9 173.3h8.9M39.4 164.3h190.4M69.8 179.5v22.9h10.2M69.8 179.5l1.3 1.9M69.8 179.5l-1.2 1.9M85.1 162.3h10.3M341.6 163.4h5.1v1.8h-5.1zM346.7 164.3h30.4M362.5 160.1h.7M362.9 160.3h.3"/>
<path d="M377.1 164.3l1.6-1.5h13.4v3h-13.4zM378.7 167.8h12.5v3.1h-12.5l-1.6-1.5zM400 173.7h3.8M69.8 192.2h10.2M69.8 197.3h10.2M72.4 189.7h7.6M72.4 194.8h7.6M72.4 199.8h7.6M72.4 187.1h7.6M80 184.6h-7.6v35.5M91.5 188.7h1.4M95.2 184.6h17.8"/>
<path d="M97.2 189.7h3.1M130.8 191.2l2 1-2 1M130.8 198.8l2 1-2 1M133.1 193.8h3.4M163.8 187.1l-2.5 2.6h-15.3M163.8 189.7l-2.5 2.5h-15.3M163.8 192.2l-2.5 2.6h-15.3M163.8 194.8l-2.5 2.5h-15.3M163.8 197.3l-2.5 2.5h-15.3M163.8 199.8l-2.5 2.6h-15.3M163.8 184.6l-2.5 2.5h-15.3M174 199.8h15.2"/>
<path d="M176.5 194.8h10.7M179 192.2h10.2M189.2 191.2l2 1-2 1M189.2 198.8l2 1-2 1M191.5 193.8h3.4M222.2 199.8l-2.5 2.6h-15.3M222.2 187.1l-2.5 2.6h-15.3M222.2 189.7l-2.5 2.5h-15.3M222.2 192.2l-2.5 2.6h-15.3M222.2 194.8l-2.5 2.5h-15.3M222.2 197.3l-2.5 2.5h-15.3M222.2 184.6l-2.5 2.5h-15.3"/>
<path d="M285.7 199.8l-2.5 2.6h-17.8M362.5 199.8h3.9M372.1 194.8h-7.7v5M384.2 194.8h3.1M24.5 216.1h13.3l1.6 1.5-1.6 1.5h-13.3zM25.4 216.5h10.4M26.9 205.9h10.9l1.6 1.6-1.6 1.5h-10.9zM27.8 206.3h8M33.1 211h4.7l1.6 1.5-1.6 1.6h-4.7zM34 211.4h1.8M39.4 207.5h40.6M72.4 215.1h5.6"/>
<path d="M80 212.5h-17.8v5.1h-22.8M80 210h-20.3v2.5h-20.3M82.3 214.1h3.1M103.5 210.5h22.2M133.1 209.1h3.1M146 210h5.1M163.8 202.4l-2.5 2.5h-15.3M168.9 219.7v1.1M169.9 217.6h-1v1.1M170.9 217.6h1.1M171.4 210h15.8M173 217.6h1"/>
<path d="M175 217.6h1.1M177.1 217.6h1M178.9 210.5h7.8M179.1 217.6h1.1M181.2 217.6h1M183.2 217.6h1.1M185.3 217.6h1M187.3 217.6h1.1M189.4 217.6h1M191.4 217.6h1.1M191.5 209.1h3.1M193.5 217.6h1"/>
<path d="M195.5 217.6h1.1M197.6 217.6h1M199.6 217.6h1.1M201.7 217.6h1M203.7 217.6h1.1M204.4 210h7.7v10.1h-30.5v7.7h7.6M205.8 217.6h1M207.8 217.6h1.1M209.9 217.6h1M211.9 217.6h1.1M214 217.6h1M216 217.6h1.1"/>
<path d="M218.1 217.6h1M220.1 217.6h1M222.2 217.6h1M222.2 202.4l-2.5 2.5h-15.3M224.2 217.6h1.1M226.3 217.6h1v1.1M227.3 219.7v1.1M250.2 206.5l1.9 1-1.9 .9M250.2 214.1l1.9 1-1.9 .9M252.5 209.1h3.3M285.7 215.1l-2.5 2.5h-17.8M285.7 217.6l-2.5 2.5h-17.8"/>
<path d="M285.7 202.4l-2.5 2.5h-17.8M285.7 207.5l-2.5 2.5h-17.8M285.7 204.9l-2.5 2.6h-17.8M285.7 210l-2.5 2.5h-17.8M285.7 212.5l-2.5 2.6h-17.8M311.1 217.6v5.6M318.7 217.6v5.6M326.3 217.6v5.6M334 217.6v5.6M341.6 217.6v5.6M349.2 217.6v5.6M356.8 217.6v5.6"/>
<path d="M364.4 217.6v5.6M372.1 217.6v5.6M379.7 217.6h-76.2v5.6M379.7 212.5l1.3 1.9M379.7 212.5l-1.3 1.9M379.7 212.5v10.7M389.8 212.5l1.3 1.9M389.8 212.5l-1.2 1.9M389.8 212.5v10.7M16.5 224.2h3.8M30.5 228.3h10.3M47 228.3h1.8"/>
<path d="M54.6 228.3h7.9M68.6 228.3h22.2M70.5 220.1h3.8M71.5 233.4h7.1M168.9 221.8v1M168.9 223.9v1M168.9 225.9v1.1M168.9 228v1.1M168.9 230.1v1.1M168.9 232.2v1.1M168.9 234.3v1M168.9 236.3v1.1"/>
<path d="M168.9 238.4v1.1M189.2 231.9l2 .9-2 1M189.2 239.5l2 1-2 .9M191.5 234.4h3.4M204.4 235.4h10.2M204.4 230.3h10.2M204.4 232.8h10.2M204.4 237.9h10.2M204.4 227.8h10.2M227.3 221.8v1M227.3 223.9v1M227.3 225.9v1.1"/>
<path d="M227.3 228v1.1M227.3 230.1v1.1M227.3 232.2v1.1M227.3 234.3v1M227.3 236.3v1.1M227.3 238.4v1.1M234.8 225.7h10.3M252.5 224.3h3.1M265.4 225.2h5.1M301.6 235.4h3.8M303.5 224.7v10.7M311.1 224.7v5.6"/>
<path d="M318.7 224.7v5.6M326.3 224.7v5.6M334 224.7v5.6M341.6 224.7v5.6M349.2 224.7v5.6M356.8 224.7v5.6M364.4 224.7v5.6M372.1 224.7v5.6M379.7 224.7v5.6h-76.2M387.9 235.4h3.9M389.8 224.7v10.7M400 224.2h3.8"/>
<path d="M71.5 253.7h7.1M71.5 243.5h7.1M168.9 257.2v1h1M168.9 240.5v1.1M168.9 242.6v1.1M168.9 244.7v1M168.9 246.7v1.1M168.9 248.8v1.1M168.9 250.9v1.1M168.9 253v1.1M168.9 255.1v1.1M170.9 258.2h1.1"/>
<path d="M173 258.2h1M175 258.2h1.1M177.1 258.2h1M179.1 258.2h1.1M181.2 258.2h1M183.2 258.2h1.1M185.3 258.2h1M187.3 258.2h1.1M189.4 258.2h1M191.4 258.2h1.1M191.5 249.7h3.1M193.5 258.2h1"/>
<path d="M195.5 258.2h1.1M197.6 258.2h1M199.6 258.2h1.1M201.7 258.2h1M203.7 258.2h1.1M204.4 240.5h10.2M204.4 243h10.2M204.4 245.5h10.2M204.4 250.6h5.1M205.8 258.2h1M207.8 258.2h1.1M209.9 258.2h1"/>
<path d="M211.9 258.2h1.1M214 258.2h1M216 258.2h1.1M218.1 258.2h1M220.1 258.2h1M222.2 258.2h1M224.2 258.2h1.1M227.3 240.5v1.1M227.3 242.6v1.1M227.3 244.7v1M227.3 246.7v1.1M227.3 248.8v1.1"/>
<path d="M227.3 250.9v1.1M227.3 253v1.1M227.3 255.1v1.1M227.3 257.2v1h-1M313.6 249.3h86.4M313.6 254.4h86.4M313.6 259.5h86.4M372.1 259.5v5.1M67.8 274.7v3.9M71.5 263.8h7.1M115.2 274.7v3.9M128.2 268.9h22.2"/>
<path d="M153.3 268.9h7.9M162.7 274.7v3.9M164.9 268.9h9.2M177 268.9h1.8M210.2 274.7v3.9M257.6 274.7v3.9M305.1 274.7v3.9M313.6 264.6h86.4M313.6 269.7h86.4M352.6 274.7v3.9M400 274.6h.1"/>
<circle cx="67.3" cy="99.8" r=".99"/>
<circle cx="69.8" cy="99.8" r=".99"/>
<circle cx="60.7" cy="123.6" r=".76"/>
<circle cx="129.8" cy="128.7" r=".99"/>
<circle cx="188.2" cy="128.7" r=".99"/>
<circle cx="249.2" cy="128.7" r=".99"/>
<circle cx="129.8" cy="144" r=".99"/>
<circle cx="188.2" cy="144" r=".99"/>
<circle cx="249.2" cy="144" r=".99"/>
<circle cx="312.7" cy="141.4" r=".99"/>
<circle cx="312.7" cy="156.7" r=".99"/>
<circle cx="96.2" cy="189.7" r=".99"/>
<circle cx="129.8" cy="194.8" r=".99"/>
<circle cx="188.2" cy="194.8" r=".99"/>
<circle cx="383.2" cy="194.8" r=".99"/>
<circle cx="79" cy="215.1" r=".99"/>
<circle cx="129.8" cy="210" r=".99"/>
<circle cx="188.2" cy="210" r=".99"/>
<circle cx="249.2" cy="210" r=".99"/>
<circle cx="188.2" cy="235.4" r=".99"/>
<circle cx="249.2" cy="225.2" r=".99"/>
<circle cx="188.2" cy="250.6" r=".99"/>
</g>
<g fill="none" stroke="#000" stroke-width=".61">
<path d="M20.3 22.1h379.7v252.6h-379.7zM64.8 100.8h22.8v15.2h-22.8zM130.8 118.6h15.2v27.9h-15.2zM189.2 118.6h15.2v27.9h-15.2zM250.2 118.6h15.2v27.9h-15.2zM313.6 131.3h15.3v27.9h-15.3zM80 182.1h15.2v35.5h-15.2zM130.8 184.6h15.2v27.9h-15.2zM189.2 184.6h15.2v27.9h-15.2zM250.2 199.8h15.2v28h-15.2zM372.1 189.7l10.1 5.1-10.1 5zM22.9 226.5h5v-5.1h36.9v5.1h59.6v45.7h-101.5z"/>
<path d="M22.9 231.6h101.5M189.2 225.2h15.2v28h-15.2zM313.6 244.3v30.4M400 244.3h-116.8v30.4"/>
</g>
<g fill="none" stroke="#000" stroke-width=".42">
<path d="M52.1 118.6h10.1l-5.1 10.1zM334 107.1h22.8v8.9h-22.8zM376.5 110.3h6.4v.6h-6.4zM377.1 108.4v1.3M379.7 108.4v1.3M382.2 108.4v1.3M22.9 236.6h101.5M43.2 221.4v50.8M52.1 221.4v50.8M22.9 257h101.5M22.9 241.7h101.5M22.9 246.8h101.5"/>
<path d="M22.9 251.9h101.5M22.9 262h101.5M22.9 267.1h101.5M27.9 272.2v-45.7h36.9v45.7"/>
<circle cx="336.5" cy="108.4" r=".25"/>
<circle cx="339" cy="108.4" r=".25"/>
<circle cx="341.6" cy="108.4" r=".25"/>
<circle cx="344.1" cy="108.4" r=".25"/>
<circle cx="346.7" cy="108.4" r=".25"/>
<circle cx="349.2" cy="108.4" r=".25"/>
<circle cx="351.7" cy="108.4" r=".25"/>
</g>
<path d="M16.5 18.2h387.3v260.4h-387.3z" fill="none" stroke="#000" stroke-width=".32"/>
<g fill="#000" stroke="#000" stroke-width=".25">
<path d="M360.1 132.5h.5v2.6h-.5zM360.1 137.6h.5v2.5h-.5zM360.1 122.4h.5v2.5h-.5zM360.1 127.4h.5v2.6h-.5zM360.1 152.8h.5v2.6h-.5zM360.1 157.9h.5v2.6h-.5zM360.1 142.7h.5v2.5h-.5zM360.1 147.8h.5v2.5h-.5zM362.4 199.6h4.1v.5h-4.1zM70.4 219.9h4v.5h-4zM301.5 235.1h4v.5h-4zM301.5 223.2h4v.5h-4z"/>
<path d="M301.5 224.2h4v.5h-4zM309.1 223.2h4v.5h-4zM309.1 224.2h4v.5h-4zM316.7 223.2h4.1v.5h-4.1zM316.7 224.2h4.1v.5h-4.1zM324.3 223.2h4.1v.5h-4.1zM324.3 224.2h4.1v.5h-4.1zM331.9 223.2h4.1v.5h-4.1zM331.9 224.2h4.1v.5h-4.1zM339.6 223.2h4v.5h-4zM339.6 224.2h4v.5h-4zM347.2 223.2h4v.5h-4z"/>
<path d="M347.2 224.2h4v.5h-4zM354.8 223.2h4.1v.5h-4.1zM354.8 224.2h4.1v.5h-4.1zM362.4 223.2h4.1v.5h-4.1zM362.4 224.2h4.1v.5h-4.1zM370 223.2h4.1v.5h-4.1zM370 224.2h4.1v.5h-4.1zM377.7 223.2h4v.5h-4zM377.7 224.2h4v.5h-4zM387.8 224.2h4.1v.5h-4.1zM387.8 223.2h4.1v.5h-4.1zM387.8 235.1h4.1v.5h-4.1z"/>
</g>
<path d="M41.9 39.8h116.8l5.1 5.1v157.5M41.9 34.8h172.7l7.6 7.6v160M41.9 29.7h233.7l10.1 10.1v177.8" fill="none" stroke="#000" stroke-width=".76"/>
<g fill="#000" stroke="#000" stroke-width=".25">
<circle cx="77.5" cy="57.6" r=".51"/>
<circle cx="80" cy="52.5" r=".51"/>
<circle cx="85.1" cy="47.5" r=".51"/>
<circle cx="67.3" cy="72.9" r=".51"/>
<circle cx="69.8" cy="67.8" r=".51"/>
<circle cx="74.9" cy="62.7" r=".51"/>
<circle cx="118.1" cy="72.9" r=".51"/>
<circle cx="123.2" cy="77.9" r=".51"/>
<circle cx="176.5" cy="72.9" r=".51"/>
<circle cx="181.6" cy="77.9" r=".51"/>
<circle cx="234.9" cy="72.9" r=".51"/>
<circle cx="242.5" cy="77.9" r=".51"/>
<circle cx="298.4" cy="72.9" r=".51"/>
<circle cx="300.9" cy="77.9" r=".51"/>
<circle cx="174" cy="105.9" r=".51"/>
<circle cx="232.4" cy="105.9" r=".51"/>
<circle cx="295.9" cy="105.9" r=".51"/>
<circle cx="115.5" cy="128.7" r=".51"/>
<circle cx="115.5" cy="133.8" r=".51"/>
<circle cx="118.1" cy="128.7" r=".51"/>
<circle cx="120.6" cy="126.2" r=".51"/>
<circle cx="174" cy="133.8" r=".51"/>
<circle cx="176.5" cy="128.7" r=".51"/>
<circle cx="232.4" cy="133.8" r=".51"/>
<circle cx="234.9" cy="128.7" r=".51"/>
<circle cx="336.5" cy="123.6" r=".51"/>
<circle cx="339" cy="128.7" r=".51"/>
<circle cx="341.6" cy="133.8" r=".51"/>
<circle cx="344.1" cy="138.9" r=".51"/>
<circle cx="171.4" cy="154.1" r=".51"/>
<circle cx="179" cy="151.6" r=".51"/>
<circle cx="237.5" cy="159.2" r=".51"/>
<circle cx="346.7" cy="144" r=".51"/>
<circle cx="349.2" cy="149" r=".51"/>
<circle cx="351.7" cy="154.1" r=".51"/>
<circle cx="354.3" cy="159.2" r=".51"/>
<circle cx="229.8" cy="164.3" r=".51"/>
<circle cx="303.5" cy="169.4" r=".51"/>
<circle cx="69.8" cy="197.3" r=".51"/>
<circle cx="69.8" cy="192.2" r=".51"/>
<circle cx="72.4" cy="194.8" r=".51"/>
<circle cx="72.4" cy="199.8" r=".51"/>
<circle cx="72.4" cy="187.1" r=".51"/>
<circle cx="72.4" cy="189.7" r=".51"/>
<circle cx="113" cy="184.6" r=".51"/>
<circle cx="174" cy="199.8" r=".51"/>
<circle cx="176.5" cy="194.8" r=".51"/>
<circle cx="179" cy="192.2" r=".51"/>
<circle cx="72.4" cy="215.1" r=".51"/>
<circle cx="171.4" cy="210" r=".51"/>
<circle cx="311.1" cy="217.6" r=".51"/>
<circle cx="318.7" cy="217.6" r=".51"/>
<circle cx="326.3" cy="217.6" r=".51"/>
<circle cx="334" cy="217.6" r=".51"/>
<circle cx="341.6" cy="217.6" r=".51"/>
<circle cx="349.2" cy="217.6" r=".51"/>
<circle cx="356.8" cy="217.6" r=".51"/>
<circle cx="364.4" cy="217.6" r=".51"/>
<circle cx="372.1" cy="217.6" r=".51"/>
<circle cx="379.7" cy="217.6" r=".51"/>
<circle cx="303.5" cy="230.3" r=".51"/>
<circle cx="311.1" cy="230.3" r=".51"/>
<circle cx="318.7" cy="230.3" r=".51"/>
<circle cx="326.3" cy="230.3" r=".51"/>
<circle cx="334" cy="230.3" r=".51"/>
<circle cx="341.6" cy="230.3" r=".51"/>
<circle cx="349.2" cy="230.3" r=".51"/>
<circle cx="356.8" cy="230.3" r=".51"/>
<circle cx="364.4" cy="230.3" r=".51"/>
<circle cx="372.1" cy="230.3" r=".51"/>
</g>
<use href="#words"/>
</svg>
